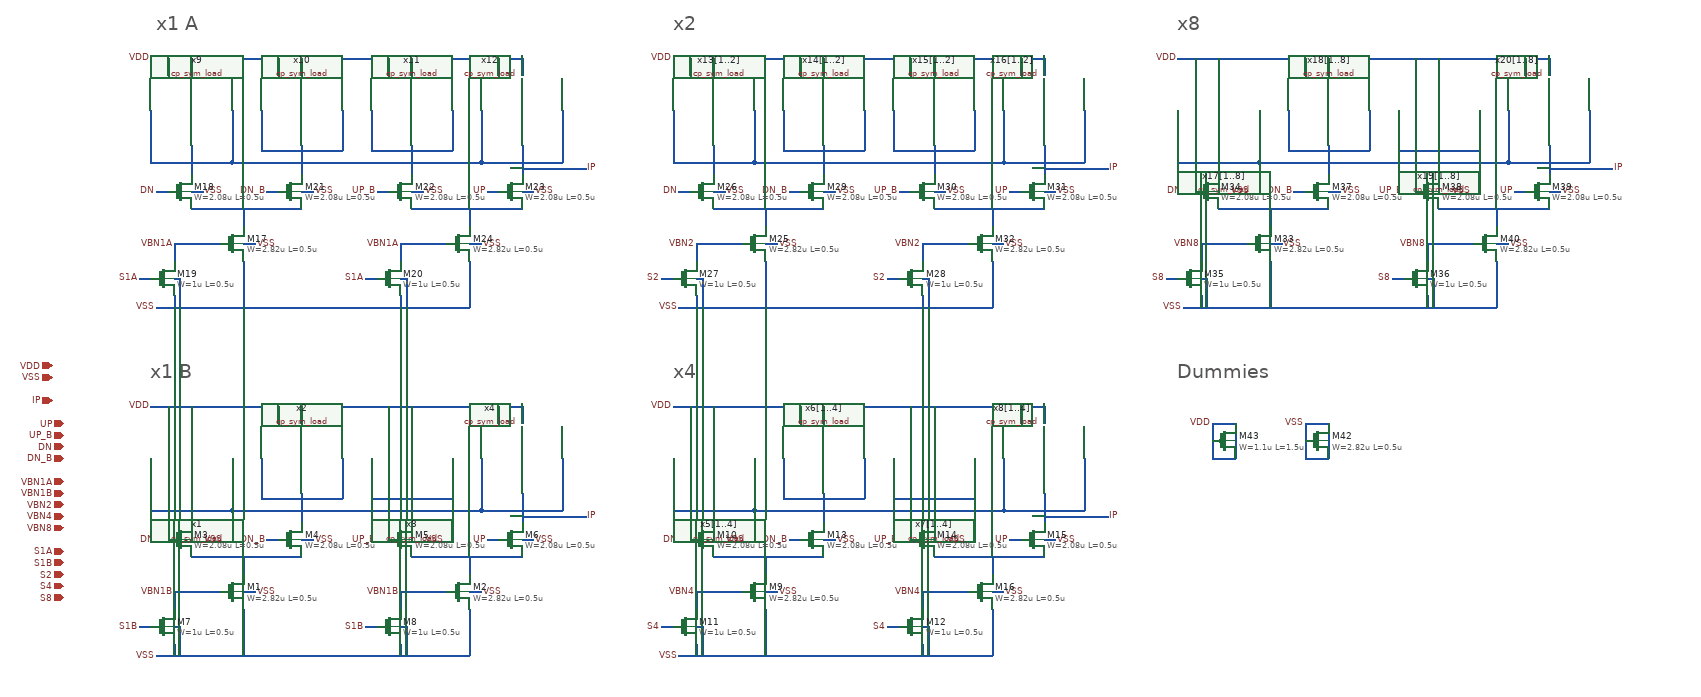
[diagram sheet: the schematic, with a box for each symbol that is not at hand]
v {xschem version=3.4.8RC file_version=1.3}
G {}
K {}
V {}
S {}
F {}
E {}
T { x1 A} 320 -1180 0 0 1 1 {}
T {x1 B} 320 -580 0 0 1 1 {}
T {x2} 1220 -1180 0 0 1 1 {}
T {x4} 1220 -580 0 0 1 1 {}
T {x8} 2090 -1180 0 0 1 1 {}
T {Dummies} 2090 -580 0 0 1 1 {}
N 390 -250 580 -250 {lab=#net1}
N 770 -250 960 -250 {lab=#net2}
N 420 -190 440 -190 {lab=VBN1B}
N 900 -280 920 -280 {lab=UP}
N 710 -280 730 -280 {lab=UP_B}
N 330 -280 350 -280 {lab=DN}
N 520 -280 540 -280 {lab=DN_B}
N 480 -250 480 -220 {lab=#net1}
N 870 -250 870 -220 {lab=#net2}
N 510 -420 510 -350 {lab=#net3}
N 510 -350 580 -350 {lab=#net3}
N 650 -420 650 -350 {lab=#net3}
N 580 -350 650 -350 {lab=#net3}
N 700 -420 700 -350 {lab=#net4}
N 700 -350 770 -350 {lab=#net4}
N 840 -420 840 -350 {lab=#net4}
N 770 -350 840 -350 {lab=#net4}
N 390 -360 390 -310 {lab=#net5}
N 580 -360 580 -310 {lab=#net3}
N 770 -360 770 -310 {lab=#net4}
N 320 -330 390 -330 {lab=#net5}
N 390 -330 460 -330 {lab=#net5}
N 320 -420 320 -330 {lab=#net5}
N 460 -420 460 -330 {lab=#net5}
N 460 -330 890 -330 {lab=#net5}
N 890 -420 890 -330 {lab=#net5}
N 960 -360 960 -310 {lab=IP}
N 320 -510 960 -510 {lab=VDD}
N 960 -510 960 -480 {lab=VDD}
N 920 -510 920 -480 {lab=VDD}
N 770 -510 770 -480 {lab=VDD}
N 730 -510 730 -480 {lab=VDD}
N 580 -510 580 -480 {lab=VDD}
N 540 -510 540 -480 {lab=VDD}
N 390 -510 390 -480 {lab=VDD}
N 350 -510 350 -480 {lab=VDD}
N 330 -80 870 -80 {lab=VSS}
N 870 -110 870 -80 {lab=VSS}
N 480 -110 480 -80 {lab=VSS}
N 390 -280 410 -280 {lab=VSS}
N 580 -280 600 -280 {lab=VSS}
N 770 -280 790 -280 {lab=VSS}
N 960 -280 980 -280 {lab=VSS}
N 480 -190 500 -190 {lab=VSS}
N 870 -190 890 -190 {lab=VSS}
N 1030 -320 1070 -320 {lab=IP}
N 960 -320 1030 -320 {lab=IP}
N 890 -330 1030 -330 {lab=#net5}
N 1030 -420 1030 -330 {lab=#net5}
N 480 -160 480 -110 {lab=VSS}
N 870 -160 870 -110 {lab=VSS}
N 360 -100 360 -80 {lab=VSS}
N 360 -190 360 -160 {lab=VBN1B}
N 360 -190 420 -190 {lab=VBN1B}
N 360 -130 370 -130 {lab=VSS}
N 370 -130 370 -80 {lab=VSS}
N 810 -190 830 -190 {lab=VBN1B}
N 750 -100 750 -80 {lab=VSS}
N 750 -190 750 -160 {lab=VBN1B}
N 750 -190 810 -190 {lab=VBN1B}
N 750 -130 760 -130 {lab=VSS}
N 760 -130 760 -80 {lab=VSS}
N 300 -130 320 -130 {lab=S1B}
N 690 -130 710 -130 {lab=S1B}
N 1290 -250 1480 -250 {lab=#net6}
N 1670 -250 1860 -250 {lab=#net7}
N 1320 -190 1340 -190 {lab=VBN4}
N 1800 -280 1820 -280 {lab=UP}
N 1610 -280 1630 -280 {lab=UP_B}
N 1230 -280 1250 -280 {lab=DN}
N 1420 -280 1440 -280 {lab=DN_B}
N 1380 -250 1380 -220 {lab=#net6}
N 1770 -250 1770 -220 {lab=#net7}
N 1410 -420 1410 -350 {lab=#net8}
N 1410 -350 1480 -350 {lab=#net8}
N 1550 -420 1550 -350 {lab=#net8}
N 1480 -350 1550 -350 {lab=#net8}
N 1600 -420 1600 -350 {lab=#net9}
N 1600 -350 1670 -350 {lab=#net9}
N 1740 -420 1740 -350 {lab=#net9}
N 1670 -350 1740 -350 {lab=#net9}
N 1290 -360 1290 -310 {lab=#net10}
N 1480 -360 1480 -310 {lab=#net8}
N 1670 -360 1670 -310 {lab=#net9}
N 1220 -330 1290 -330 {lab=#net10}
N 1290 -330 1360 -330 {lab=#net10}
N 1220 -420 1220 -330 {lab=#net10}
N 1360 -420 1360 -330 {lab=#net10}
N 1360 -330 1790 -330 {lab=#net10}
N 1790 -420 1790 -330 {lab=#net10}
N 1860 -360 1860 -310 {lab=IP}
N 1220 -510 1860 -510 {lab=VDD}
N 1860 -510 1860 -480 {lab=VDD}
N 1820 -510 1820 -480 {lab=VDD}
N 1670 -510 1670 -480 {lab=VDD}
N 1630 -510 1630 -480 {lab=VDD}
N 1480 -510 1480 -480 {lab=VDD}
N 1440 -510 1440 -480 {lab=VDD}
N 1290 -510 1290 -480 {lab=VDD}
N 1250 -510 1250 -480 {lab=VDD}
N 1230 -80 1770 -80 {lab=VSS}
N 1770 -110 1770 -80 {lab=VSS}
N 1380 -110 1380 -80 {lab=VSS}
N 1290 -280 1310 -280 {lab=VSS}
N 1480 -280 1500 -280 {lab=VSS}
N 1670 -280 1690 -280 {lab=VSS}
N 1860 -280 1880 -280 {lab=VSS}
N 1380 -190 1400 -190 {lab=VSS}
N 1770 -190 1790 -190 {lab=VSS}
N 1930 -320 1970 -320 {lab=IP}
N 1860 -320 1930 -320 {lab=IP}
N 1790 -330 1930 -330 {lab=#net10}
N 1930 -420 1930 -330 {lab=#net10}
N 1380 -160 1380 -110 {lab=VSS}
N 1770 -160 1770 -110 {lab=VSS}
N 1260 -100 1260 -80 {lab=VSS}
N 1260 -190 1260 -160 {lab=VBN4}
N 1260 -190 1320 -190 {lab=VBN4}
N 1260 -130 1270 -130 {lab=VSS}
N 1270 -130 1270 -80 {lab=VSS}
N 1710 -190 1730 -190 {lab=VBN4}
N 1650 -100 1650 -80 {lab=VSS}
N 1650 -190 1650 -160 {lab=VBN4}
N 1650 -190 1710 -190 {lab=VBN4}
N 1650 -130 1660 -130 {lab=VSS}
N 1660 -130 1660 -80 {lab=VSS}
N 1200 -130 1220 -130 {lab=S4}
N 1590 -130 1610 -130 {lab=S4}
N 390 -850 580 -850 {lab=#net11}
N 770 -850 960 -850 {lab=#net12}
N 420 -790 440 -790 {lab=VBN1A}
N 900 -880 920 -880 {lab=UP}
N 710 -880 730 -880 {lab=UP_B}
N 330 -880 350 -880 {lab=DN}
N 520 -880 540 -880 {lab=DN_B}
N 480 -850 480 -820 {lab=#net11}
N 870 -850 870 -820 {lab=#net12}
N 510 -1020 510 -950 {lab=#net13}
N 510 -950 580 -950 {lab=#net13}
N 650 -1020 650 -950 {lab=#net13}
N 580 -950 650 -950 {lab=#net13}
N 700 -1020 700 -950 {lab=#net14}
N 700 -950 770 -950 {lab=#net14}
N 840 -1020 840 -950 {lab=#net14}
N 770 -950 840 -950 {lab=#net14}
N 390 -960 390 -910 {lab=#net15}
N 580 -960 580 -910 {lab=#net13}
N 770 -960 770 -910 {lab=#net14}
N 320 -930 390 -930 {lab=#net15}
N 390 -930 460 -930 {lab=#net15}
N 320 -1020 320 -930 {lab=#net15}
N 460 -1020 460 -930 {lab=#net15}
N 460 -930 890 -930 {lab=#net15}
N 890 -1020 890 -930 {lab=#net15}
N 960 -960 960 -910 {lab=IP}
N 320 -1110 960 -1110 {lab=VDD}
N 960 -1110 960 -1080 {lab=VDD}
N 920 -1110 920 -1080 {lab=VDD}
N 770 -1110 770 -1080 {lab=VDD}
N 730 -1110 730 -1080 {lab=VDD}
N 580 -1110 580 -1080 {lab=VDD}
N 540 -1110 540 -1080 {lab=VDD}
N 390 -1110 390 -1080 {lab=VDD}
N 350 -1110 350 -1080 {lab=VDD}
N 330 -680 870 -680 {lab=VSS}
N 870 -710 870 -680 {lab=VSS}
N 480 -710 480 -680 {lab=VSS}
N 390 -880 410 -880 {lab=VSS}
N 580 -880 600 -880 {lab=VSS}
N 770 -880 790 -880 {lab=VSS}
N 960 -880 980 -880 {lab=VSS}
N 480 -790 500 -790 {lab=VSS}
N 870 -790 890 -790 {lab=VSS}
N 1030 -920 1070 -920 {lab=IP}
N 960 -920 1030 -920 {lab=IP}
N 890 -930 1030 -930 {lab=#net15}
N 1030 -1020 1030 -930 {lab=#net15}
N 480 -760 480 -710 {lab=VSS}
N 870 -760 870 -710 {lab=VSS}
N 360 -700 360 -680 {lab=VSS}
N 360 -790 360 -760 {lab=VBN1A}
N 360 -790 420 -790 {lab=VBN1A}
N 360 -730 370 -730 {lab=VSS}
N 370 -730 370 -680 {lab=VSS}
N 810 -790 830 -790 {lab=VBN1A}
N 750 -700 750 -680 {lab=VSS}
N 750 -790 750 -760 {lab=VBN1A}
N 750 -790 810 -790 {lab=VBN1A}
N 750 -730 760 -730 {lab=VSS}
N 760 -730 760 -680 {lab=VSS}
N 300 -730 320 -730 {lab=S1A}
N 690 -730 710 -730 {lab=S1A}
N 1290 -850 1480 -850 {lab=#net16}
N 1670 -850 1860 -850 {lab=#net17}
N 1320 -790 1340 -790 {lab=VBN2}
N 1800 -880 1820 -880 {lab=UP}
N 1610 -880 1630 -880 {lab=UP_B}
N 1230 -880 1250 -880 {lab=DN}
N 1420 -880 1440 -880 {lab=DN_B}
N 1380 -850 1380 -820 {lab=#net16}
N 1770 -850 1770 -820 {lab=#net17}
N 1410 -1020 1410 -950 {lab=#net18}
N 1410 -950 1480 -950 {lab=#net18}
N 1550 -1020 1550 -950 {lab=#net18}
N 1480 -950 1550 -950 {lab=#net18}
N 1600 -1020 1600 -950 {lab=#net19}
N 1600 -950 1670 -950 {lab=#net19}
N 1740 -1020 1740 -950 {lab=#net19}
N 1670 -950 1740 -950 {lab=#net19}
N 1290 -960 1290 -910 {lab=#net20}
N 1480 -960 1480 -910 {lab=#net18}
N 1670 -960 1670 -910 {lab=#net19}
N 1220 -930 1290 -930 {lab=#net20}
N 1290 -930 1360 -930 {lab=#net20}
N 1220 -1020 1220 -930 {lab=#net20}
N 1360 -1020 1360 -930 {lab=#net20}
N 1360 -930 1790 -930 {lab=#net20}
N 1790 -1020 1790 -930 {lab=#net20}
N 1860 -960 1860 -910 {lab=IP}
N 1220 -1110 1860 -1110 {lab=VDD}
N 1860 -1110 1860 -1080 {lab=VDD}
N 1820 -1110 1820 -1080 {lab=VDD}
N 1670 -1110 1670 -1080 {lab=VDD}
N 1630 -1110 1630 -1080 {lab=VDD}
N 1480 -1110 1480 -1080 {lab=VDD}
N 1440 -1110 1440 -1080 {lab=VDD}
N 1290 -1110 1290 -1080 {lab=VDD}
N 1250 -1110 1250 -1080 {lab=VDD}
N 1230 -680 1770 -680 {lab=VSS}
N 1770 -710 1770 -680 {lab=VSS}
N 1380 -710 1380 -680 {lab=VSS}
N 1290 -880 1310 -880 {lab=VSS}
N 1480 -880 1500 -880 {lab=VSS}
N 1670 -880 1690 -880 {lab=VSS}
N 1860 -880 1880 -880 {lab=VSS}
N 1380 -790 1400 -790 {lab=VSS}
N 1770 -790 1790 -790 {lab=VSS}
N 1930 -920 1970 -920 {lab=IP}
N 1860 -920 1930 -920 {lab=IP}
N 1790 -930 1930 -930 {lab=#net20}
N 1930 -1020 1930 -930 {lab=#net20}
N 1380 -760 1380 -710 {lab=VSS}
N 1770 -760 1770 -710 {lab=VSS}
N 1260 -700 1260 -680 {lab=VSS}
N 1260 -790 1260 -760 {lab=VBN2}
N 1260 -790 1320 -790 {lab=VBN2}
N 1260 -730 1270 -730 {lab=VSS}
N 1270 -730 1270 -680 {lab=VSS}
N 1710 -790 1730 -790 {lab=VBN2}
N 1650 -700 1650 -680 {lab=VSS}
N 1650 -790 1650 -760 {lab=VBN2}
N 1650 -790 1710 -790 {lab=VBN2}
N 1650 -730 1660 -730 {lab=VSS}
N 1660 -730 1660 -680 {lab=VSS}
N 1200 -730 1220 -730 {lab=S2}
N 1590 -730 1610 -730 {lab=S2}
N 2160 -850 2350 -850 {lab=#net21}
N 2540 -850 2730 -850 {lab=#net22}
N 2190 -790 2210 -790 {lab=VBN8}
N 2670 -880 2690 -880 {lab=UP}
N 2480 -880 2500 -880 {lab=UP_B}
N 2100 -880 2120 -880 {lab=DN}
N 2290 -880 2310 -880 {lab=DN_B}
N 2250 -850 2250 -820 {lab=#net21}
N 2640 -850 2640 -820 {lab=#net22}
N 2280 -1020 2280 -950 {lab=#net23}
N 2280 -950 2350 -950 {lab=#net23}
N 2420 -1020 2420 -950 {lab=#net23}
N 2350 -950 2420 -950 {lab=#net23}
N 2470 -1020 2470 -950 {lab=#net24}
N 2470 -950 2540 -950 {lab=#net24}
N 2610 -1020 2610 -950 {lab=#net24}
N 2540 -950 2610 -950 {lab=#net24}
N 2160 -960 2160 -910 {lab=#net25}
N 2350 -960 2350 -910 {lab=#net23}
N 2540 -960 2540 -910 {lab=#net24}
N 2090 -930 2160 -930 {lab=#net25}
N 2160 -930 2230 -930 {lab=#net25}
N 2090 -1020 2090 -930 {lab=#net25}
N 2230 -1020 2230 -930 {lab=#net25}
N 2230 -930 2660 -930 {lab=#net25}
N 2660 -1020 2660 -930 {lab=#net25}
N 2730 -960 2730 -910 {lab=IP}
N 2090 -1110 2730 -1110 {lab=VDD}
N 2730 -1110 2730 -1080 {lab=VDD}
N 2690 -1110 2690 -1080 {lab=VDD}
N 2540 -1110 2540 -1080 {lab=VDD}
N 2500 -1110 2500 -1080 {lab=VDD}
N 2350 -1110 2350 -1080 {lab=VDD}
N 2310 -1110 2310 -1080 {lab=VDD}
N 2160 -1110 2160 -1080 {lab=VDD}
N 2120 -1110 2120 -1080 {lab=VDD}
N 2100 -680 2640 -680 {lab=VSS}
N 2640 -710 2640 -680 {lab=VSS}
N 2250 -710 2250 -680 {lab=VSS}
N 2160 -880 2180 -880 {lab=VSS}
N 2350 -880 2370 -880 {lab=VSS}
N 2540 -880 2560 -880 {lab=VSS}
N 2730 -880 2750 -880 {lab=VSS}
N 2250 -790 2270 -790 {lab=VSS}
N 2640 -790 2660 -790 {lab=VSS}
N 2800 -920 2840 -920 {lab=IP}
N 2730 -920 2800 -920 {lab=IP}
N 2660 -930 2800 -930 {lab=#net25}
N 2800 -1020 2800 -930 {lab=#net25}
N 2250 -760 2250 -710 {lab=VSS}
N 2640 -760 2640 -710 {lab=VSS}
N 2130 -700 2130 -680 {lab=VSS}
N 2130 -790 2130 -760 {lab=VBN8}
N 2130 -790 2190 -790 {lab=VBN8}
N 2130 -730 2140 -730 {lab=VSS}
N 2140 -730 2140 -680 {lab=VSS}
N 2580 -790 2600 -790 {lab=VBN8}
N 2520 -700 2520 -680 {lab=VSS}
N 2520 -790 2520 -760 {lab=VBN8}
N 2520 -790 2580 -790 {lab=VBN8}
N 2520 -730 2530 -730 {lab=VSS}
N 2530 -730 2530 -680 {lab=VSS}
N 2070 -730 2090 -730 {lab=S8}
N 2460 -730 2480 -730 {lab=S8}
N 2150 -480 2190 -480 {lab=VDD}
N 2150 -480 2150 -420 {lab=VDD}
N 2150 -420 2190 -420 {lab=VDD}
N 2190 -480 2190 -420 {lab=VDD}
N 2310 -480 2350 -480 {lab=#net26}
N 2310 -480 2310 -420 {lab=#net26}
N 2310 -420 2350 -420 {lab=#net26}
N 2350 -480 2350 -420 {lab=#net26}
C {devices/title.sym} 160 -30 0 0 {name=l5 author="Muhammad Farhan"}
C {lab_pin.sym} 360 -190 0 0 {name=p1 sig_type=std_logic lab=VBN1B}
C {lab_pin.sym} 900 -280 0 0 {name=p3 sig_type=std_logic lab=UP}
C {lab_pin.sym} 710 -280 0 0 {name=p4 sig_type=std_logic lab=UP_B}
C {lab_pin.sym} 330 -280 0 0 {name=p5 sig_type=std_logic lab=DN}
C {lab_pin.sym} 520 -280 0 0 {name=p6 sig_type=std_logic lab=DN_B}
C {libs/core_analog/cp_sym_load/cp_sym_load.sym} 390 -420 0 0 {name=x1}
C {libs/core_analog/cp_sym_load/cp_sym_load.sym} 580 -420 0 0 {name=x2}
C {libs/core_analog/cp_sym_load/cp_sym_load.sym} 770 -420 0 0 {name=x3}
C {libs/core_analog/cp_sym_load/cp_sym_load.sym} 960 -420 0 0 {name=x4}
C {lab_pin.sym} 320 -510 0 0 {name=p7 sig_type=std_logic lab=VDD}
C {lab_pin.sym} 330 -80 0 0 {name=p8 sig_type=std_logic lab=VSS}
C {lab_pin.sym} 410 -280 0 1 {name=p9 sig_type=std_logic lab=VSS}
C {lab_pin.sym} 600 -280 0 1 {name=p10 sig_type=std_logic lab=VSS}
C {lab_pin.sym} 790 -280 0 1 {name=p11 sig_type=std_logic lab=VSS}
C {lab_pin.sym} 980 -280 0 1 {name=p12 sig_type=std_logic lab=VSS}
C {lab_pin.sym} 500 -190 0 1 {name=p13 sig_type=std_logic lab=VSS}
C {lab_pin.sym} 890 -190 0 1 {name=p14 sig_type=std_logic lab=VSS}
C {iopin.sym} 150 -580 0 0 {name=p15 lab=VDD}
C {iopin.sym} 150 -560 0 0 {name=p16 lab=VSS
}
C {ipin.sym} 170 -480 0 0 {name=p17 lab=UP}
C {ipin.sym} 170 -460 0 0 {name=p18 lab=UP_B}
C {ipin.sym} 170 -440 0 0 {name=p19 lab=DN}
C {ipin.sym} 170 -420 0 0 {name=p20 lab=DN_B}
C {ipin.sym} 170 -380 0 0 {name=p21 lab=VBN1A}
C {lab_pin.sym} 1070 -320 0 1 {name=p22 sig_type=std_logic lab=IP}
C {iopin.sym} 150 -520 0 0 {name=p23 lab=IP
}
C {symbols/nfet_03v3.sym} 460 -190 0 0 {name=M1
L=0.5u
W=2.82u
nf=1
m=4
ad="'int((nf+1)/2) * W/nf * 0.18u'"
pd="'2*int((nf+1)/2) * (W/nf + 0.18u)'"
as="'int((nf+2)/2) * W/nf * 0.18u'"
ps="'2*int((nf+2)/2) * (W/nf + 0.18u)'"
nrd="'0.18u / W'" nrs="'0.18u / W'"
sa=0 sb=0 sd=0
model=nfet_03v3
spiceprefix=X
}
C {symbols/nfet_03v3.sym} 370 -280 0 0 {name=M3
L=0.5u
W=2.08u
nf=1
m=1
ad="'int((nf+1)/2) * W/nf * 0.18u'"
pd="'2*int((nf+1)/2) * (W/nf + 0.18u)'"
as="'int((nf+2)/2) * W/nf * 0.18u'"
ps="'2*int((nf+2)/2) * (W/nf + 0.18u)'"
nrd="'0.18u / W'" nrs="'0.18u / W'"
sa=0 sb=0 sd=0
model=nfet_03v3
spiceprefix=X
}
C {symbols/nfet_03v3.sym} 340 -130 0 0 {name=M7
L=0.5u
W=1u
nf=1
m=1
ad="'int((nf+1)/2) * W/nf * 0.18u'"
pd="'2*int((nf+1)/2) * (W/nf + 0.18u)'"
as="'int((nf+2)/2) * W/nf * 0.18u'"
ps="'2*int((nf+2)/2) * (W/nf + 0.18u)'"
nrd="'0.18u / W'" nrs="'0.18u / W'"
sa=0 sb=0 sd=0
model=nfet_03v3
spiceprefix=X
}
C {lab_pin.sym} 750 -190 0 0 {name=p2 sig_type=std_logic lab=VBN1B}
C {symbols/nfet_03v3.sym} 730 -130 0 0 {name=M8
L=0.5u
W=1u
nf=1
m=1
ad="'int((nf+1)/2) * W/nf * 0.18u'"
pd="'2*int((nf+1)/2) * (W/nf + 0.18u)'"
as="'int((nf+2)/2) * W/nf * 0.18u'"
ps="'2*int((nf+2)/2) * (W/nf + 0.18u)'"
nrd="'0.18u / W'" nrs="'0.18u / W'"
sa=0 sb=0 sd=0
model=nfet_03v3
spiceprefix=X
}
C {lab_pin.sym} 300 -130 0 0 {name=p24 sig_type=std_logic lab=S1B}
C {ipin.sym} 170 -260 0 0 {name=p26 lab=S1A}
C {symbols/nfet_03v3.sym} 560 -280 0 0 {name=M4
L=0.5u
W=2.08u
nf=1
m=1
ad="'int((nf+1)/2) * W/nf * 0.18u'"
pd="'2*int((nf+1)/2) * (W/nf + 0.18u)'"
as="'int((nf+2)/2) * W/nf * 0.18u'"
ps="'2*int((nf+2)/2) * (W/nf + 0.18u)'"
nrd="'0.18u / W'" nrs="'0.18u / W'"
sa=0 sb=0 sd=0
model=nfet_03v3
spiceprefix=X
}
C {symbols/nfet_03v3.sym} 750 -280 0 0 {name=M5
L=0.5u
W=2.08u
nf=1
m=1
ad="'int((nf+1)/2) * W/nf * 0.18u'"
pd="'2*int((nf+1)/2) * (W/nf + 0.18u)'"
as="'int((nf+2)/2) * W/nf * 0.18u'"
ps="'2*int((nf+2)/2) * (W/nf + 0.18u)'"
nrd="'0.18u / W'" nrs="'0.18u / W'"
sa=0 sb=0 sd=0
model=nfet_03v3
spiceprefix=X
}
C {symbols/nfet_03v3.sym} 940 -280 0 0 {name=M6
L=0.5u
W=2.08u
nf=1
m=1
ad="'int((nf+1)/2) * W/nf * 0.18u'"
pd="'2*int((nf+1)/2) * (W/nf + 0.18u)'"
as="'int((nf+2)/2) * W/nf * 0.18u'"
ps="'2*int((nf+2)/2) * (W/nf + 0.18u)'"
nrd="'0.18u / W'" nrs="'0.18u / W'"
sa=0 sb=0 sd=0
model=nfet_03v3
spiceprefix=X
}
C {symbols/nfet_03v3.sym} 850 -190 0 0 {name=M2
L=0.5u
W=2.82u
nf=1
m=4
ad="'int((nf+1)/2) * W/nf * 0.18u'"
pd="'2*int((nf+1)/2) * (W/nf + 0.18u)'"
as="'int((nf+2)/2) * W/nf * 0.18u'"
ps="'2*int((nf+2)/2) * (W/nf + 0.18u)'"
nrd="'0.18u / W'" nrs="'0.18u / W'"
sa=0 sb=0 sd=0
model=nfet_03v3
spiceprefix=X
}
C {lab_pin.sym} 1260 -190 0 0 {name=p27 sig_type=std_logic lab=VBN4}
C {lab_pin.sym} 1800 -280 0 0 {name=p28 sig_type=std_logic lab=UP}
C {lab_pin.sym} 1610 -280 0 0 {name=p29 sig_type=std_logic lab=UP_B}
C {lab_pin.sym} 1230 -280 0 0 {name=p30 sig_type=std_logic lab=DN}
C {lab_pin.sym} 1420 -280 0 0 {name=p31 sig_type=std_logic lab=DN_B}
C {libs/core_analog/cp_sym_load/cp_sym_load.sym} 1290 -420 0 0 {name=x5[1..4]}
C {libs/core_analog/cp_sym_load/cp_sym_load.sym} 1480 -420 0 0 {name=x6[1..4]}
C {libs/core_analog/cp_sym_load/cp_sym_load.sym} 1670 -420 0 0 {name=x7[1..4]}
C {libs/core_analog/cp_sym_load/cp_sym_load.sym} 1860 -420 0 0 {name=x8[1..4]}
C {lab_pin.sym} 1220 -510 0 0 {name=p32 sig_type=std_logic lab=VDD}
C {lab_pin.sym} 1230 -80 0 0 {name=p33 sig_type=std_logic lab=VSS}
C {lab_pin.sym} 1310 -280 0 1 {name=p34 sig_type=std_logic lab=VSS}
C {lab_pin.sym} 1500 -280 0 1 {name=p35 sig_type=std_logic lab=VSS}
C {lab_pin.sym} 1690 -280 0 1 {name=p36 sig_type=std_logic lab=VSS}
C {lab_pin.sym} 1880 -280 0 1 {name=p37 sig_type=std_logic lab=VSS}
C {lab_pin.sym} 1400 -190 0 1 {name=p38 sig_type=std_logic lab=VSS}
C {lab_pin.sym} 1790 -190 0 1 {name=p39 sig_type=std_logic lab=VSS}
C {lab_pin.sym} 1970 -320 0 1 {name=p40 sig_type=std_logic lab=IP}
C {symbols/nfet_03v3.sym} 1360 -190 0 0 {name=M9
L=0.5u
W=2.82u
nf=1
m=16
ad="'int((nf+1)/2) * W/nf * 0.18u'"
pd="'2*int((nf+1)/2) * (W/nf + 0.18u)'"
as="'int((nf+2)/2) * W/nf * 0.18u'"
ps="'2*int((nf+2)/2) * (W/nf + 0.18u)'"
nrd="'0.18u / W'" nrs="'0.18u / W'"
sa=0 sb=0 sd=0
model=nfet_03v3
spiceprefix=X
}
C {symbols/nfet_03v3.sym} 1270 -280 0 0 {name=M10
L=0.5u
W=2.08u
nf=1
m=4
ad="'int((nf+1)/2) * W/nf * 0.18u'"
pd="'2*int((nf+1)/2) * (W/nf + 0.18u)'"
as="'int((nf+2)/2) * W/nf * 0.18u'"
ps="'2*int((nf+2)/2) * (W/nf + 0.18u)'"
nrd="'0.18u / W'" nrs="'0.18u / W'"
sa=0 sb=0 sd=0
model=nfet_03v3
spiceprefix=X
}
C {symbols/nfet_03v3.sym} 1240 -130 0 0 {name=M11
L=0.5u
W=1u
nf=1
m=4
ad="'int((nf+1)/2) * W/nf * 0.18u'"
pd="'2*int((nf+1)/2) * (W/nf + 0.18u)'"
as="'int((nf+2)/2) * W/nf * 0.18u'"
ps="'2*int((nf+2)/2) * (W/nf + 0.18u)'"
nrd="'0.18u / W'" nrs="'0.18u / W'"
sa=0 sb=0 sd=0
model=nfet_03v3
spiceprefix=X
}
C {lab_pin.sym} 1650 -190 0 0 {name=p41 sig_type=std_logic lab=VBN4}
C {symbols/nfet_03v3.sym} 1630 -130 0 0 {name=M12
L=0.5u
W=1u
nf=1
m=4
ad="'int((nf+1)/2) * W/nf * 0.18u'"
pd="'2*int((nf+1)/2) * (W/nf + 0.18u)'"
as="'int((nf+2)/2) * W/nf * 0.18u'"
ps="'2*int((nf+2)/2) * (W/nf + 0.18u)'"
nrd="'0.18u / W'" nrs="'0.18u / W'"
sa=0 sb=0 sd=0
model=nfet_03v3
spiceprefix=X
}
C {lab_pin.sym} 1200 -130 0 0 {name=p42 sig_type=std_logic lab=S4}
C {lab_pin.sym} 1590 -130 0 0 {name=p43 sig_type=std_logic lab=S4}
C {symbols/nfet_03v3.sym} 1460 -280 0 0 {name=M13
L=0.5u
W=2.08u
nf=1
m=4
ad="'int((nf+1)/2) * W/nf * 0.18u'"
pd="'2*int((nf+1)/2) * (W/nf + 0.18u)'"
as="'int((nf+2)/2) * W/nf * 0.18u'"
ps="'2*int((nf+2)/2) * (W/nf + 0.18u)'"
nrd="'0.18u / W'" nrs="'0.18u / W'"
sa=0 sb=0 sd=0
model=nfet_03v3
spiceprefix=X
}
C {symbols/nfet_03v3.sym} 1650 -280 0 0 {name=M14
L=0.5u
W=2.08u
nf=1
m=4
ad="'int((nf+1)/2) * W/nf * 0.18u'"
pd="'2*int((nf+1)/2) * (W/nf + 0.18u)'"
as="'int((nf+2)/2) * W/nf * 0.18u'"
ps="'2*int((nf+2)/2) * (W/nf + 0.18u)'"
nrd="'0.18u / W'" nrs="'0.18u / W'"
sa=0 sb=0 sd=0
model=nfet_03v3
spiceprefix=X
}
C {symbols/nfet_03v3.sym} 1840 -280 0 0 {name=M15
L=0.5u
W=2.08u
nf=1
m=4
ad="'int((nf+1)/2) * W/nf * 0.18u'"
pd="'2*int((nf+1)/2) * (W/nf + 0.18u)'"
as="'int((nf+2)/2) * W/nf * 0.18u'"
ps="'2*int((nf+2)/2) * (W/nf + 0.18u)'"
nrd="'0.18u / W'" nrs="'0.18u / W'"
sa=0 sb=0 sd=0
model=nfet_03v3
spiceprefix=X
}
C {symbols/nfet_03v3.sym} 1750 -190 0 0 {name=M16
L=0.5u
W=2.82u
nf=1
m=16
ad="'int((nf+1)/2) * W/nf * 0.18u'"
pd="'2*int((nf+1)/2) * (W/nf + 0.18u)'"
as="'int((nf+2)/2) * W/nf * 0.18u'"
ps="'2*int((nf+2)/2) * (W/nf + 0.18u)'"
nrd="'0.18u / W'" nrs="'0.18u / W'"
sa=0 sb=0 sd=0
model=nfet_03v3
spiceprefix=X
}
C {lab_pin.sym} 900 -880 0 0 {name=p45 sig_type=std_logic lab=UP}
C {lab_pin.sym} 710 -880 0 0 {name=p46 sig_type=std_logic lab=UP_B}
C {lab_pin.sym} 330 -880 0 0 {name=p47 sig_type=std_logic lab=DN}
C {lab_pin.sym} 520 -880 0 0 {name=p48 sig_type=std_logic lab=DN_B}
C {libs/core_analog/cp_sym_load/cp_sym_load.sym} 390 -1020 0 0 {name=x9}
C {libs/core_analog/cp_sym_load/cp_sym_load.sym} 580 -1020 0 0 {name=x10}
C {libs/core_analog/cp_sym_load/cp_sym_load.sym} 770 -1020 0 0 {name=x11}
C {libs/core_analog/cp_sym_load/cp_sym_load.sym} 960 -1020 0 0 {name=x12}
C {lab_pin.sym} 320 -1110 0 0 {name=p49 sig_type=std_logic lab=VDD}
C {lab_pin.sym} 330 -680 0 0 {name=p50 sig_type=std_logic lab=VSS}
C {lab_pin.sym} 410 -880 0 1 {name=p51 sig_type=std_logic lab=VSS}
C {lab_pin.sym} 600 -880 0 1 {name=p52 sig_type=std_logic lab=VSS}
C {lab_pin.sym} 790 -880 0 1 {name=p53 sig_type=std_logic lab=VSS}
C {lab_pin.sym} 980 -880 0 1 {name=p54 sig_type=std_logic lab=VSS}
C {lab_pin.sym} 500 -790 0 1 {name=p55 sig_type=std_logic lab=VSS}
C {lab_pin.sym} 890 -790 0 1 {name=p56 sig_type=std_logic lab=VSS}
C {lab_pin.sym} 1070 -920 0 1 {name=p57 sig_type=std_logic lab=IP}
C {symbols/nfet_03v3.sym} 460 -790 0 0 {name=M17
L=0.5u
W=2.82u
nf=1
m=4
ad="'int((nf+1)/2) * W/nf * 0.18u'"
pd="'2*int((nf+1)/2) * (W/nf + 0.18u)'"
as="'int((nf+2)/2) * W/nf * 0.18u'"
ps="'2*int((nf+2)/2) * (W/nf + 0.18u)'"
nrd="'0.18u / W'" nrs="'0.18u / W'"
sa=0 sb=0 sd=0
model=nfet_03v3
spiceprefix=X
}
C {symbols/nfet_03v3.sym} 370 -880 0 0 {name=M18
L=0.5u
W=2.08u
nf=1
m=1
ad="'int((nf+1)/2) * W/nf * 0.18u'"
pd="'2*int((nf+1)/2) * (W/nf + 0.18u)'"
as="'int((nf+2)/2) * W/nf * 0.18u'"
ps="'2*int((nf+2)/2) * (W/nf + 0.18u)'"
nrd="'0.18u / W'" nrs="'0.18u / W'"
sa=0 sb=0 sd=0
model=nfet_03v3
spiceprefix=X
}
C {symbols/nfet_03v3.sym} 340 -730 0 0 {name=M19
L=0.5u
W=1u
nf=1
m=1
ad="'int((nf+1)/2) * W/nf * 0.18u'"
pd="'2*int((nf+1)/2) * (W/nf + 0.18u)'"
as="'int((nf+2)/2) * W/nf * 0.18u'"
ps="'2*int((nf+2)/2) * (W/nf + 0.18u)'"
nrd="'0.18u / W'" nrs="'0.18u / W'"
sa=0 sb=0 sd=0
model=nfet_03v3
spiceprefix=X
}
C {lab_pin.sym} 750 -790 0 0 {name=p58 sig_type=std_logic lab=VBN1A}
C {symbols/nfet_03v3.sym} 730 -730 0 0 {name=M20
L=0.5u
W=1u
nf=1
m=1
ad="'int((nf+1)/2) * W/nf * 0.18u'"
pd="'2*int((nf+1)/2) * (W/nf + 0.18u)'"
as="'int((nf+2)/2) * W/nf * 0.18u'"
ps="'2*int((nf+2)/2) * (W/nf + 0.18u)'"
nrd="'0.18u / W'" nrs="'0.18u / W'"
sa=0 sb=0 sd=0
model=nfet_03v3
spiceprefix=X
}
C {lab_pin.sym} 300 -730 0 0 {name=p59 sig_type=std_logic lab=S1A}
C {lab_pin.sym} 690 -730 0 0 {name=p60 sig_type=std_logic lab=S1A}
C {symbols/nfet_03v3.sym} 560 -880 0 0 {name=M21
L=0.5u
W=2.08u
nf=1
m=1
ad="'int((nf+1)/2) * W/nf * 0.18u'"
pd="'2*int((nf+1)/2) * (W/nf + 0.18u)'"
as="'int((nf+2)/2) * W/nf * 0.18u'"
ps="'2*int((nf+2)/2) * (W/nf + 0.18u)'"
nrd="'0.18u / W'" nrs="'0.18u / W'"
sa=0 sb=0 sd=0
model=nfet_03v3
spiceprefix=X
}
C {symbols/nfet_03v3.sym} 750 -880 0 0 {name=M22
L=0.5u
W=2.08u
nf=1
m=1
ad="'int((nf+1)/2) * W/nf * 0.18u'"
pd="'2*int((nf+1)/2) * (W/nf + 0.18u)'"
as="'int((nf+2)/2) * W/nf * 0.18u'"
ps="'2*int((nf+2)/2) * (W/nf + 0.18u)'"
nrd="'0.18u / W'" nrs="'0.18u / W'"
sa=0 sb=0 sd=0
model=nfet_03v3
spiceprefix=X
}
C {symbols/nfet_03v3.sym} 940 -880 0 0 {name=M23
L=0.5u
W=2.08u
nf=1
m=1
ad="'int((nf+1)/2) * W/nf * 0.18u'"
pd="'2*int((nf+1)/2) * (W/nf + 0.18u)'"
as="'int((nf+2)/2) * W/nf * 0.18u'"
ps="'2*int((nf+2)/2) * (W/nf + 0.18u)'"
nrd="'0.18u / W'" nrs="'0.18u / W'"
sa=0 sb=0 sd=0
model=nfet_03v3
spiceprefix=X
}
C {symbols/nfet_03v3.sym} 850 -790 0 0 {name=M24
L=0.5u
W=2.82u
nf=1
m=4
ad="'int((nf+1)/2) * W/nf * 0.18u'"
pd="'2*int((nf+1)/2) * (W/nf + 0.18u)'"
as="'int((nf+2)/2) * W/nf * 0.18u'"
ps="'2*int((nf+2)/2) * (W/nf + 0.18u)'"
nrd="'0.18u / W'" nrs="'0.18u / W'"
sa=0 sb=0 sd=0
model=nfet_03v3
spiceprefix=X
}
C {lab_pin.sym} 1260 -790 0 0 {name=p61 sig_type=std_logic lab=VBN2}
C {lab_pin.sym} 1800 -880 0 0 {name=p62 sig_type=std_logic lab=UP}
C {lab_pin.sym} 1610 -880 0 0 {name=p63 sig_type=std_logic lab=UP_B}
C {lab_pin.sym} 1230 -880 0 0 {name=p64 sig_type=std_logic lab=DN}
C {lab_pin.sym} 1420 -880 0 0 {name=p65 sig_type=std_logic lab=DN_B}
C {libs/core_analog/cp_sym_load/cp_sym_load.sym} 1290 -1020 0 0 {name=x13[1..2]}
C {libs/core_analog/cp_sym_load/cp_sym_load.sym} 1480 -1020 0 0 {name=x14[1..2]}
C {libs/core_analog/cp_sym_load/cp_sym_load.sym} 1670 -1020 0 0 {name=x15[1..2]}
C {libs/core_analog/cp_sym_load/cp_sym_load.sym} 1860 -1020 0 0 {name=x16[1..2]}
C {lab_pin.sym} 1220 -1110 0 0 {name=p66 sig_type=std_logic lab=VDD}
C {lab_pin.sym} 1230 -680 0 0 {name=p67 sig_type=std_logic lab=VSS}
C {lab_pin.sym} 1310 -880 0 1 {name=p68 sig_type=std_logic lab=VSS}
C {lab_pin.sym} 1500 -880 0 1 {name=p69 sig_type=std_logic lab=VSS}
C {lab_pin.sym} 1690 -880 0 1 {name=p70 sig_type=std_logic lab=VSS}
C {lab_pin.sym} 1880 -880 0 1 {name=p71 sig_type=std_logic lab=VSS}
C {lab_pin.sym} 1400 -790 0 1 {name=p72 sig_type=std_logic lab=VSS}
C {lab_pin.sym} 1790 -790 0 1 {name=p73 sig_type=std_logic lab=VSS}
C {lab_pin.sym} 1970 -920 0 1 {name=p74 sig_type=std_logic lab=IP}
C {symbols/nfet_03v3.sym} 1360 -790 0 0 {name=M25
L=0.5u
W=2.82u
nf=1
m=8
ad="'int((nf+1)/2) * W/nf * 0.18u'"
pd="'2*int((nf+1)/2) * (W/nf + 0.18u)'"
as="'int((nf+2)/2) * W/nf * 0.18u'"
ps="'2*int((nf+2)/2) * (W/nf + 0.18u)'"
nrd="'0.18u / W'" nrs="'0.18u / W'"
sa=0 sb=0 sd=0
model=nfet_03v3
spiceprefix=X
}
C {symbols/nfet_03v3.sym} 1270 -880 0 0 {name=M26
L=0.5u
W=2.08u
nf=1
m=2
ad="'int((nf+1)/2) * W/nf * 0.18u'"
pd="'2*int((nf+1)/2) * (W/nf + 0.18u)'"
as="'int((nf+2)/2) * W/nf * 0.18u'"
ps="'2*int((nf+2)/2) * (W/nf + 0.18u)'"
nrd="'0.18u / W'" nrs="'0.18u / W'"
sa=0 sb=0 sd=0
model=nfet_03v3
spiceprefix=X
}
C {symbols/nfet_03v3.sym} 1240 -730 0 0 {name=M27
L=0.5u
W=1u
nf=1
m=2
ad="'int((nf+1)/2) * W/nf * 0.18u'"
pd="'2*int((nf+1)/2) * (W/nf + 0.18u)'"
as="'int((nf+2)/2) * W/nf * 0.18u'"
ps="'2*int((nf+2)/2) * (W/nf + 0.18u)'"
nrd="'0.18u / W'" nrs="'0.18u / W'"
sa=0 sb=0 sd=0
model=nfet_03v3
spiceprefix=X
}
C {lab_pin.sym} 1650 -790 0 0 {name=p75 sig_type=std_logic lab=VBN2}
C {symbols/nfet_03v3.sym} 1630 -730 0 0 {name=M28
L=0.5u
W=1u
nf=1
m=2
ad="'int((nf+1)/2) * W/nf * 0.18u'"
pd="'2*int((nf+1)/2) * (W/nf + 0.18u)'"
as="'int((nf+2)/2) * W/nf * 0.18u'"
ps="'2*int((nf+2)/2) * (W/nf + 0.18u)'"
nrd="'0.18u / W'" nrs="'0.18u / W'"
sa=0 sb=0 sd=0
model=nfet_03v3
spiceprefix=X
}
C {lab_pin.sym} 1200 -730 0 0 {name=p76 sig_type=std_logic lab=S2}
C {lab_pin.sym} 1590 -730 0 0 {name=p77 sig_type=std_logic lab=S2}
C {symbols/nfet_03v3.sym} 1460 -880 0 0 {name=M29
L=0.5u
W=2.08u
nf=1
m=2
ad="'int((nf+1)/2) * W/nf * 0.18u'"
pd="'2*int((nf+1)/2) * (W/nf + 0.18u)'"
as="'int((nf+2)/2) * W/nf * 0.18u'"
ps="'2*int((nf+2)/2) * (W/nf + 0.18u)'"
nrd="'0.18u / W'" nrs="'0.18u / W'"
sa=0 sb=0 sd=0
model=nfet_03v3
spiceprefix=X
}
C {symbols/nfet_03v3.sym} 1650 -880 0 0 {name=M30
L=0.5u
W=2.08u
nf=1
m=2
ad="'int((nf+1)/2) * W/nf * 0.18u'"
pd="'2*int((nf+1)/2) * (W/nf + 0.18u)'"
as="'int((nf+2)/2) * W/nf * 0.18u'"
ps="'2*int((nf+2)/2) * (W/nf + 0.18u)'"
nrd="'0.18u / W'" nrs="'0.18u / W'"
sa=0 sb=0 sd=0
model=nfet_03v3
spiceprefix=X
}
C {symbols/nfet_03v3.sym} 1840 -880 0 0 {name=M31
L=0.5u
W=2.08u
nf=1
m=2
ad="'int((nf+1)/2) * W/nf * 0.18u'"
pd="'2*int((nf+1)/2) * (W/nf + 0.18u)'"
as="'int((nf+2)/2) * W/nf * 0.18u'"
ps="'2*int((nf+2)/2) * (W/nf + 0.18u)'"
nrd="'0.18u / W'" nrs="'0.18u / W'"
sa=0 sb=0 sd=0
model=nfet_03v3
spiceprefix=X
}
C {symbols/nfet_03v3.sym} 1750 -790 0 0 {name=M32
L=0.5u
W=2.82u
nf=1
m=8
ad="'int((nf+1)/2) * W/nf * 0.18u'"
pd="'2*int((nf+1)/2) * (W/nf + 0.18u)'"
as="'int((nf+2)/2) * W/nf * 0.18u'"
ps="'2*int((nf+2)/2) * (W/nf + 0.18u)'"
nrd="'0.18u / W'" nrs="'0.18u / W'"
sa=0 sb=0 sd=0
model=nfet_03v3
spiceprefix=X
}
C {lab_pin.sym} 2130 -790 0 0 {name=p78 sig_type=std_logic lab=VBN8}
C {lab_pin.sym} 2670 -880 0 0 {name=p79 sig_type=std_logic lab=UP}
C {lab_pin.sym} 2480 -880 0 0 {name=p80 sig_type=std_logic lab=UP_B}
C {lab_pin.sym} 2100 -880 0 0 {name=p81 sig_type=std_logic lab=DN}
C {lab_pin.sym} 2290 -880 0 0 {name=p82 sig_type=std_logic lab=DN_B}
C {libs/core_analog/cp_sym_load/cp_sym_load.sym} 2160 -1020 0 0 {name=x17[1..8]}
C {libs/core_analog/cp_sym_load/cp_sym_load.sym} 2350 -1020 0 0 {name=x18[1..8]}
C {libs/core_analog/cp_sym_load/cp_sym_load.sym} 2540 -1020 0 0 {name=x19[1..8]}
C {libs/core_analog/cp_sym_load/cp_sym_load.sym} 2730 -1020 0 0 {name=x20[1..8]}
C {lab_pin.sym} 2090 -1110 0 0 {name=p83 sig_type=std_logic lab=VDD}
C {lab_pin.sym} 2100 -680 0 0 {name=p84 sig_type=std_logic lab=VSS}
C {lab_pin.sym} 2180 -880 0 1 {name=p85 sig_type=std_logic lab=VSS}
C {lab_pin.sym} 2370 -880 0 1 {name=p86 sig_type=std_logic lab=VSS}
C {lab_pin.sym} 2560 -880 0 1 {name=p87 sig_type=std_logic lab=VSS}
C {lab_pin.sym} 2750 -880 0 1 {name=p88 sig_type=std_logic lab=VSS}
C {lab_pin.sym} 2270 -790 0 1 {name=p89 sig_type=std_logic lab=VSS}
C {lab_pin.sym} 2660 -790 0 1 {name=p90 sig_type=std_logic lab=VSS}
C {lab_pin.sym} 2840 -920 0 1 {name=p91 sig_type=std_logic lab=IP}
C {symbols/nfet_03v3.sym} 2230 -790 0 0 {name=M33
L=0.5u
W=2.82u
nf=1
m=32
ad="'int((nf+1)/2) * W/nf * 0.18u'"
pd="'2*int((nf+1)/2) * (W/nf + 0.18u)'"
as="'int((nf+2)/2) * W/nf * 0.18u'"
ps="'2*int((nf+2)/2) * (W/nf + 0.18u)'"
nrd="'0.18u / W'" nrs="'0.18u / W'"
sa=0 sb=0 sd=0
model=nfet_03v3
spiceprefix=X
}
C {symbols/nfet_03v3.sym} 2140 -880 0 0 {name=M34
L=0.5u
W=2.08u
nf=1
m=8
ad="'int((nf+1)/2) * W/nf * 0.18u'"
pd="'2*int((nf+1)/2) * (W/nf + 0.18u)'"
as="'int((nf+2)/2) * W/nf * 0.18u'"
ps="'2*int((nf+2)/2) * (W/nf + 0.18u)'"
nrd="'0.18u / W'" nrs="'0.18u / W'"
sa=0 sb=0 sd=0
model=nfet_03v3
spiceprefix=X
}
C {symbols/nfet_03v3.sym} 2110 -730 0 0 {name=M35
L=0.5u
W=1u
nf=1
m=8
ad="'int((nf+1)/2) * W/nf * 0.18u'"
pd="'2*int((nf+1)/2) * (W/nf + 0.18u)'"
as="'int((nf+2)/2) * W/nf * 0.18u'"
ps="'2*int((nf+2)/2) * (W/nf + 0.18u)'"
nrd="'0.18u / W'" nrs="'0.18u / W'"
sa=0 sb=0 sd=0
model=nfet_03v3
spiceprefix=X
}
C {lab_pin.sym} 2520 -790 0 0 {name=p92 sig_type=std_logic lab=VBN8}
C {symbols/nfet_03v3.sym} 2500 -730 0 0 {name=M36
L=0.5u
W=1u
nf=1
m=8
ad="'int((nf+1)/2) * W/nf * 0.18u'"
pd="'2*int((nf+1)/2) * (W/nf + 0.18u)'"
as="'int((nf+2)/2) * W/nf * 0.18u'"
ps="'2*int((nf+2)/2) * (W/nf + 0.18u)'"
nrd="'0.18u / W'" nrs="'0.18u / W'"
sa=0 sb=0 sd=0
model=nfet_03v3
spiceprefix=X
}
C {lab_pin.sym} 2070 -730 0 0 {name=p93 sig_type=std_logic lab=S8}
C {lab_pin.sym} 2460 -730 0 0 {name=p94 sig_type=std_logic lab=S8}
C {symbols/nfet_03v3.sym} 2330 -880 0 0 {name=M37
L=0.5u
W=2.08u
nf=1
m=8
ad="'int((nf+1)/2) * W/nf * 0.18u'"
pd="'2*int((nf+1)/2) * (W/nf + 0.18u)'"
as="'int((nf+2)/2) * W/nf * 0.18u'"
ps="'2*int((nf+2)/2) * (W/nf + 0.18u)'"
nrd="'0.18u / W'" nrs="'0.18u / W'"
sa=0 sb=0 sd=0
model=nfet_03v3
spiceprefix=X
}
C {symbols/nfet_03v3.sym} 2520 -880 0 0 {name=M38
L=0.5u
W=2.08u
nf=1
m=8
ad="'int((nf+1)/2) * W/nf * 0.18u'"
pd="'2*int((nf+1)/2) * (W/nf + 0.18u)'"
as="'int((nf+2)/2) * W/nf * 0.18u'"
ps="'2*int((nf+2)/2) * (W/nf + 0.18u)'"
nrd="'0.18u / W'" nrs="'0.18u / W'"
sa=0 sb=0 sd=0
model=nfet_03v3
spiceprefix=X
}
C {symbols/nfet_03v3.sym} 2710 -880 0 0 {name=M39
L=0.5u
W=2.08u
nf=1
m=8
ad="'int((nf+1)/2) * W/nf * 0.18u'"
pd="'2*int((nf+1)/2) * (W/nf + 0.18u)'"
as="'int((nf+2)/2) * W/nf * 0.18u'"
ps="'2*int((nf+2)/2) * (W/nf + 0.18u)'"
nrd="'0.18u / W'" nrs="'0.18u / W'"
sa=0 sb=0 sd=0
model=nfet_03v3
spiceprefix=X
}
C {symbols/nfet_03v3.sym} 2620 -790 0 0 {name=M40
L=0.5u
W=2.82u
nf=1
m=32
ad="'int((nf+1)/2) * W/nf * 0.18u'"
pd="'2*int((nf+1)/2) * (W/nf + 0.18u)'"
as="'int((nf+2)/2) * W/nf * 0.18u'"
ps="'2*int((nf+2)/2) * (W/nf + 0.18u)'"
nrd="'0.18u / W'" nrs="'0.18u / W'"
sa=0 sb=0 sd=0
model=nfet_03v3
spiceprefix=X
}
C {lab_pin.sym} 360 -790 0 0 {name=p44 sig_type=std_logic lab=VBN1A}
C {lab_pin.sym} 690 -130 0 0 {name=p25 sig_type=std_logic lab=S1B}
C {ipin.sym} 170 -360 0 0 {name=p95 lab=VBN1B}
C {ipin.sym} 170 -340 0 0 {name=p96 lab=VBN2}
C {ipin.sym} 170 -320 0 0 {name=p97 lab=VBN4}
C {ipin.sym} 170 -300 0 0 {name=p98 lab=VBN8}
C {ipin.sym} 170 -240 0 0 {name=p99 lab=S1B}
C {ipin.sym} 170 -220 0 0 {name=p100 lab=S2}
C {ipin.sym} 170 -200 0 0 {name=p101 lab=S4}
C {ipin.sym} 170 -180 0 0 {name=p102 lab=S8}
C {lab_pin.sym} 2150 -480 0 0 {name=p103 sig_type=std_logic lab=VDD}
C {symbols/nfet_03v3.sym} 2330 -450 0 0 {name=M42
L=0.5u
W=2.82u
nf=1
m=8
ad="'int((nf+1)/2) * W/nf * 0.18u'"
pd="'2*int((nf+1)/2) * (W/nf + 0.18u)'"
as="'int((nf+2)/2) * W/nf * 0.18u'"
ps="'2*int((nf+2)/2) * (W/nf + 0.18u)'"
nrd="'0.18u / W'" nrs="'0.18u / W'"
sa=0 sb=0 sd=0
model=nfet_03v3
spiceprefix=X
}
C {symbols/pfet_03v3.sym} 2170 -450 0 0 {name=M43
L=1.5u
W=1.1u
nf=1
m=16
ad="'int((nf+1)/2) * W/nf * 0.18u'"
pd="'2*int((nf+1)/2) * (W/nf + 0.18u)'"
as="'int((nf+2)/2) * W/nf * 0.18u'"
ps="'2*int((nf+2)/2) * (W/nf + 0.18u)'"
nrd="'0.18u / W'" nrs="'0.18u / W'"
sa=0 sb=0 sd=0
model=pfet_03v3
spiceprefix=X
}
C {lab_pin.sym} 2310 -480 0 0 {name=p104 sig_type=std_logic lab=VSS}
